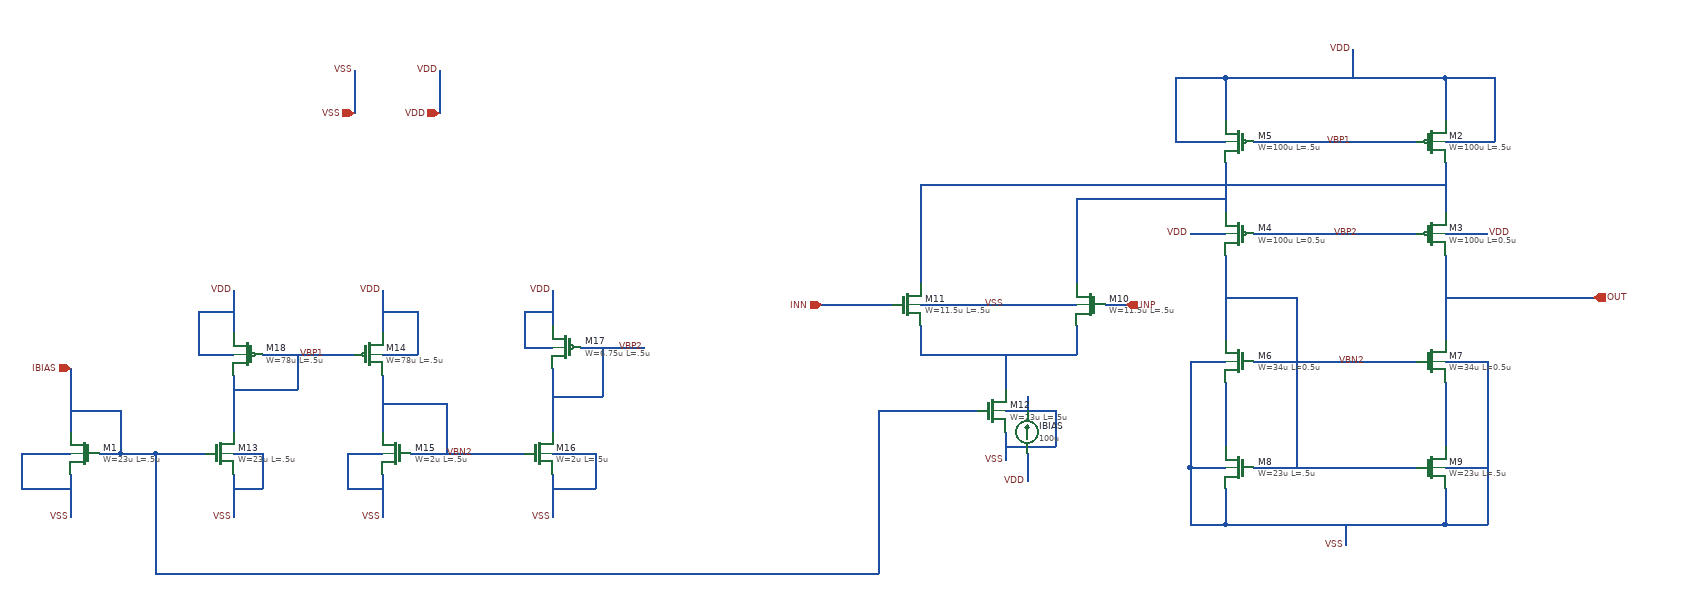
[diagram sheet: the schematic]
v {xschem version=3.4.7 file_version=1.2}
G {}
K {}
V {}
S {}
E {}
P 4 1 -990 -70 {}
P 4 1 1330 -40 {}
P 4 1 -910 -60 {}
N -410 -400 -410 -340 {lab=VDD}
N -530 -400 -530 -340 {lab=VSS}
N -930 50 -930 90 {lab=IBIAS}
N -930 90 -930 110 {lab=IBIAS}
N -930 80 -860 80 {lab=IBIAS}
N -860 80 -860 140 {lab=IBIAS}
N -890 140 -860 140 {lab=IBIAS}
N -860 140 -830 140 {lab=IBIAS}
N -930 170 -930 210 {lab=VSS}
N -1000 140 -930 140 {lab=VSS}
N -1000 140 -1000 190 {lab=VSS}
N -1000 190 -930 190 {lab=VSS}
N -930 210 -930 230 {lab=VSS}
N 700 -270 700 -200 {lab=#net1}
N 1010 -270 1010 -200 {lab=#net2}
N 740 -170 970 -170 {lab=VBP2}
N 700 -140 700 -20 {lab=#net3}
N 1010 -140 1010 -20 {lab=OUT}
N 1010 -80 1180 -80 {lab=OUT}
N 740 10 970 10 {lab=VBN2}
N 740 160 970 160 {lab=#net3}
N 1010 40 1010 100 {lab=#net4}
N 1010 100 1010 130 {lab=#net4}
N 700 40 700 130 {lab=#net5}
N 700 190 700 240 {lab=VSS}
N 700 240 1010 240 {lab=VSS}
N 1010 190 1010 240 {lab=VSS}
N 870 240 870 270 {lab=VSS}
N 700 -390 700 -330 {lab=VDD}
N 700 -390 1010 -390 {lab=VDD}
N 1010 -390 1010 -330 {lab=VDD}
N 880 -430 880 -390 {lab=VDD}
N 270 -240 1010 -240 {lab=#net2}
N 490 -220 490 -100 {lab=#net1}
N 490 -220 700 -220 {lab=#net1}
N 270 0 490 0 {lab=#net6}
N 490 -40 490 0 {lab=#net6}
N 390 0 390 50 {lab=#net6}
N 390 110 390 150 {lab=VSS}
N 290 80 350 80 {lab=IBIAS}
N 390 80 460 80 {lab=VSS}
N 460 80 460 130 {lab=VSS}
N 390 130 460 130 {lab=VSS}
N 270 -70 490 -70 {lab=VSS}
N 650 160 700 160 {lab=VSS}
N 650 160 650 240 {lab=VSS}
N 650 240 700 240 {lab=VSS}
N 650 10 700 10 {lab=VSS}
N 650 10 650 160 {lab=VSS}
N 1010 10 1070 10 {lab=VSS}
N 1010 240 1070 240 {lab=VSS}
N 1070 10 1070 240 {lab=VSS}
N 1010 160 1070 160 {lab=VSS}
N 650 -170 700 -170 {lab=VDD}
N 1010 -170 1070 -170 {lab=VDD}
N 1010 -300 1080 -300 {lab=VDD}
N 1080 -390 1080 -300 {lab=VDD}
N 1010 -390 1080 -390 {lab=VDD}
N 640 -300 700 -300 {lab=VDD}
N 630 -300 640 -300 {lab=VDD}
N 630 -390 630 -300 {lab=VDD}
N 630 -390 700 -390 {lab=VDD}
N -700 30 -700 120 {lab=VBP1}
N -700 -70 -700 -30 {lab=VDD}
N -930 20 -930 50 {lab=IBIAS}
N -700 -90 -700 -70 {lab=VDD}
N -750 0 -700 0 {lab=VDD}
N -750 -60 -750 0 {lab=VDD}
N -750 -60 -700 -60 {lab=VDD}
N -660 0 -530 0 {lab=VBP1}
N -700 50 -610 50 {lab=VBP1}
N -610 0 -610 50 {lab=VBP1}
N -830 140 -810 140 {lab=IBIAS}
N -810 140 -760 140 {lab=IBIAS}
N 270 -240 270 -100 {lab=#net2}
N 270 -40 270 0 {lab=#net6}
N -700 180 -700 230 {lab=VSS}
N 740 -300 970 -300 {lab=VBP1}
N 700 -80 800 -80 {lab=#net3}
N 800 -80 800 160 {lab=#net3}
N 130 -70 230 -70 {lab=INN}
N 530 -70 550 -70 {lab=INP}
N 550 -70 560 -70 {lab=INP}
N -700 170 -700 180 {lab=VSS}
N -700 140 -660 140 {lab=VSS}
N -660 140 -660 190 {lab=VSS}
N -700 190 -660 190 {lab=VSS}
N 1180 -80 1220 -80 {lab=OUT}
N -490 -90 -490 -30 {lab=VDD}
N -490 0 -440 0 {lab=VDD}
N -440 -60 -440 0 {lab=VDD}
N -490 -60 -440 -60 {lab=VDD}
N -490 30 -490 110 {lab=VBN2}
N -490 170 -490 230 {lab=VSS}
N -540 140 -490 140 {lab=VSS}
N -540 140 -540 190 {lab=VSS}
N -540 190 -490 190 {lab=VSS}
N -450 140 -290 140 {lab=VBN2}
N -250 20 -250 110 {lab=VBP2}
N -250 170 -250 230 {lab=VSS}
N -250 140 -190 140 {lab=VSS}
N -190 140 -190 190 {lab=VSS}
N -250 190 -190 190 {lab=VSS}
N -250 -90 -250 -40 {lab=VDD}
N -290 -10 -250 -10 {lab=VDD}
N -290 -60 -290 -10 {lab=VDD}
N -290 -60 -250 -60 {lab=VDD}
N -210 -10 -120 -10 {lab=VBP2}
N -490 70 -400 70 {lab=VBN2}
N -400 70 -400 140 {lab=VBN2}
N -250 60 -180 60 {lab=VBP2}
N -180 -10 -180 60 {lab=VBP2}
N -760 140 -740 140 {lab=IBIAS}
N -810 140 -810 310 {lab=IBIAS}
N -810 310 210 310 {lab=IBIAS}
N 210 80 210 310 {lab=IBIAS}
N 210 80 290 80 {lab=IBIAS}
N 420 60 420 80 {lab=#net1}
N 420 140 420 180 {lab=VDD}
C {lab_pin.sym} -410 -400 0 0 {name=p1 sig_type=std_logic lab=VDD}
C {lab_pin.sym} -530 -400 0 0 {name=p3 sig_type=std_logic lab=VSS}
C {symbols/nfet_03v3.sym} -910 140 0 1 {name=M1
L=.5u
W=23u
nf=1
m=1
ad="'int((nf+1)/2) * W/nf * 0.18u'"
pd="'2*int((nf+1)/2) * (W/nf + 0.18u)'"
as="'int((nf+2)/2) * W/nf * 0.18u'"
ps="'2*int((nf+2)/2) * (W/nf + 0.18u)'"
nrd="'0.18u / W'" nrs="'0.18u / W'"
sa=0 sb=0 sd=0
model=nfet_03v3
spiceprefix=X
}
C {lab_pin.sym} -930 230 0 0 {name=p5 sig_type=std_logic lab=VSS}
C {symbols/pfet_03v3.sym} 990 -300 0 0 {name=M2
L=.5u
W=100u
nf=1
m=1.5
ad="'int((nf+1)/2) * W/nf * 0.18u'"
pd="'2*int((nf+1)/2) * (W/nf + 0.18u)'"
as="'int((nf+2)/2) * W/nf * 0.18u'"
ps="'2*int((nf+2)/2) * (W/nf + 0.18u)'"
nrd="'0.18u / W'" nrs="'0.18u / W'"
sa=0 sb=0 sd=0
model=pfet_03v3
spiceprefix=X
}
C {symbols/pfet_03v3.sym} 990 -170 0 0 {name=M3
L=0.5u
W=100u
nf=1
m=1
ad="'int((nf+1)/2) * W/nf * 0.18u'"
pd="'2*int((nf+1)/2) * (W/nf + 0.18u)'"
as="'int((nf+2)/2) * W/nf * 0.18u'"
ps="'2*int((nf+2)/2) * (W/nf + 0.18u)'"
nrd="'0.18u / W'" nrs="'0.18u / W'"
sa=0 sb=0 sd=0
model=pfet_03v3
spiceprefix=X
}
C {symbols/pfet_03v3.sym} 720 -170 0 1 {name=M4
L=0.5u
W=100u
nf=1
m=1
ad="'int((nf+1)/2) * W/nf * 0.18u'"
pd="'2*int((nf+1)/2) * (W/nf + 0.18u)'"
as="'int((nf+2)/2) * W/nf * 0.18u'"
ps="'2*int((nf+2)/2) * (W/nf + 0.18u)'"
nrd="'0.18u / W'" nrs="'0.18u / W'"
sa=0 sb=0 sd=0
model=pfet_03v3
spiceprefix=X
}
C {symbols/pfet_03v3.sym} 720 -300 0 1 {name=M5
L=.5u
W=100u
nf=1
m=1.5
ad="'int((nf+1)/2) * W/nf * 0.18u'"
pd="'2*int((nf+1)/2) * (W/nf + 0.18u)'"
as="'int((nf+2)/2) * W/nf * 0.18u'"
ps="'2*int((nf+2)/2) * (W/nf + 0.18u)'"
nrd="'0.18u / W'" nrs="'0.18u / W'"
sa=0 sb=0 sd=0
model=pfet_03v3
spiceprefix=X
}
C {symbols/nfet_03v3.sym} 720 10 0 1 {name=M6
L=0.5u
W=34u
nf=1
m=1
ad="'int((nf+1)/2) * W/nf * 0.18u'"
pd="'2*int((nf+1)/2) * (W/nf + 0.18u)'"
as="'int((nf+2)/2) * W/nf * 0.18u'"
ps="'2*int((nf+2)/2) * (W/nf + 0.18u)'"
nrd="'0.18u / W'" nrs="'0.18u / W'"
sa=0 sb=0 sd=0
model=nfet_03v3
spiceprefix=X
}
C {symbols/nfet_03v3.sym} 990 10 0 0 {name=M7
L=0.5u
W=34u
nf=1
m=1
ad="'int((nf+1)/2) * W/nf * 0.18u'"
pd="'2*int((nf+1)/2) * (W/nf + 0.18u)'"
as="'int((nf+2)/2) * W/nf * 0.18u'"
ps="'2*int((nf+2)/2) * (W/nf + 0.18u)'"
nrd="'0.18u / W'" nrs="'0.18u / W'"
sa=0 sb=0 sd=0
model=nfet_03v3
spiceprefix=X
}
C {symbols/nfet_03v3.sym} 720 160 0 1 {name=M8
L=.5u
W=23u
nf=1
m=2
ad="'int((nf+1)/2) * W/nf * 0.18u'"
pd="'2*int((nf+1)/2) * (W/nf + 0.18u)'"
as="'int((nf+2)/2) * W/nf * 0.18u'"
ps="'2*int((nf+2)/2) * (W/nf + 0.18u)'"
nrd="'0.18u / W'" nrs="'0.18u / W'"
sa=0 sb=0 sd=0
model=nfet_03v3
spiceprefix=X
}
C {symbols/nfet_03v3.sym} 990 160 0 0 {name=M9
L=.5u
W=23u
nf=1
m=2
ad="'int((nf+1)/2) * W/nf * 0.18u'"
pd="'2*int((nf+1)/2) * (W/nf + 0.18u)'"
as="'int((nf+2)/2) * W/nf * 0.18u'"
ps="'2*int((nf+2)/2) * (W/nf + 0.18u)'"
nrd="'0.18u / W'" nrs="'0.18u / W'"
sa=0 sb=0 sd=0
model=nfet_03v3
spiceprefix=X
}
C {lab_pin.sym} 870 270 0 0 {name=p7 sig_type=std_logic lab=VSS}
C {lab_pin.sym} 880 -430 0 0 {name=p8 sig_type=std_logic lab=VDD}
C {symbols/nfet_03v3.sym} 510 -70 0 1 {name=M10
L=.5u
W=11.5u
nf=1
m=1
ad="'int((nf+1)/2) * W/nf * 0.18u'"
pd="'2*int((nf+1)/2) * (W/nf + 0.18u)'"
as="'int((nf+2)/2) * W/nf * 0.18u'"
ps="'2*int((nf+2)/2) * (W/nf + 0.18u)'"
nrd="'0.18u / W'" nrs="'0.18u / W'"
sa=0 sb=0 sd=0
model=nfet_03v3
spiceprefix=X
}
C {symbols/nfet_03v3.sym} 370 80 0 0 {name=M12
L=.5u
W=23u
nf=1
m=1
ad="'int((nf+1)/2) * W/nf * 0.18u'"
pd="'2*int((nf+1)/2) * (W/nf + 0.18u)'"
as="'int((nf+2)/2) * W/nf * 0.18u'"
ps="'2*int((nf+2)/2) * (W/nf + 0.18u)'"
nrd="'0.18u / W'" nrs="'0.18u / W'"
sa=0 sb=0 sd=0
model=nfet_03v3
spiceprefix=X
}
C {lab_pin.sym} 390 150 0 0 {name=p10 sig_type=std_logic lab=VSS}
C {lab_pin.sym} 390 -70 1 0 {name=p18 sig_type=std_logic lab=VSS}
C {lab_pin.sym} 650 -170 0 0 {name=p19 sig_type=std_logic lab=VDD}
C {lab_pin.sym} 1070 -170 0 1 {name=p20 sig_type=std_logic lab=VDD}
C {symbols/pfet_03v3.sym} -680 0 0 1 {name=M18
L=.5u
W=78u
nf=1
m=1
ad="'int((nf+1)/2) * W/nf * 0.18u'"
pd="'2*int((nf+1)/2) * (W/nf + 0.18u)'"
as="'int((nf+2)/2) * W/nf * 0.18u'"
ps="'2*int((nf+2)/2) * (W/nf + 0.18u)'"
nrd="'0.18u / W'" nrs="'0.18u / W'"
sa=0 sb=0 sd=0
model=pfet_03v3
spiceprefix=X
}
C {lab_pin.sym} -700 -90 0 0 {name=p31 sig_type=std_logic lab=VDD}
C {lab_pin.sym} -570 0 1 0 {name=p33 sig_type=std_logic lab=VBP1}
C {symbols/nfet_03v3.sym} 250 -70 0 0 {name=M11
L=.5u
W=11.5u
nf=1
m=1
ad="'int((nf+1)/2) * W/nf * 0.18u'"
pd="'2*int((nf+1)/2) * (W/nf + 0.18u)'"
as="'int((nf+2)/2) * W/nf * 0.18u'"
ps="'2*int((nf+2)/2) * (W/nf + 0.18u)'"
nrd="'0.18u / W'" nrs="'0.18u / W'"
sa=0 sb=0 sd=0
model=nfet_03v3
spiceprefix=X
}
C {lab_pin.sym} -700 230 0 0 {name=p12 sig_type=std_logic lab=VSS}
C {lab_pin.sym} 880 -300 1 0 {name=p13 sig_type=std_logic lab=VBP1}
C {symbols/nfet_03v3.sym} -720 140 0 0 {name=M13
L=.5u
W=23u
nf=1
m=1
ad="'int((nf+1)/2) * W/nf * 0.18u'"
pd="'2*int((nf+1)/2) * (W/nf + 0.18u)'"
as="'int((nf+2)/2) * W/nf * 0.18u'"
ps="'2*int((nf+2)/2) * (W/nf + 0.18u)'"
nrd="'0.18u / W'" nrs="'0.18u / W'"
sa=0 sb=0 sd=0
model=nfet_03v3
spiceprefix=X
}
C {symbols/pfet_03v3.sym} -510 0 0 0 {name=M14
L=.5u
W=78u
nf=1
m=1
ad="'int((nf+1)/2) * W/nf * 0.18u'"
pd="'2*int((nf+1)/2) * (W/nf + 0.18u)'"
as="'int((nf+2)/2) * W/nf * 0.18u'"
ps="'2*int((nf+2)/2) * (W/nf + 0.18u)'"
nrd="'0.18u / W'" nrs="'0.18u / W'"
sa=0 sb=0 sd=0
model=pfet_03v3
spiceprefix=X
}
C {lab_pin.sym} -490 -90 0 0 {name=p21 sig_type=std_logic lab=VDD}
C {symbols/nfet_03v3.sym} -470 140 0 1 {name=M15
L=.5u
W=2u
nf=1
m=1
ad="'int((nf+1)/2) * W/nf * 0.18u'"
pd="'2*int((nf+1)/2) * (W/nf + 0.18u)'"
as="'int((nf+2)/2) * W/nf * 0.18u'"
ps="'2*int((nf+2)/2) * (W/nf + 0.18u)'"
nrd="'0.18u / W'" nrs="'0.18u / W'"
sa=0 sb=0 sd=0
model=nfet_03v3
spiceprefix=X
}
C {lab_pin.sym} -490 230 0 0 {name=p22 sig_type=std_logic lab=VSS}
C {symbols/nfet_03v3.sym} -270 140 0 0 {name=M16
L=.5u
W=2u
nf=1
m=1
ad="'int((nf+1)/2) * W/nf * 0.18u'"
pd="'2*int((nf+1)/2) * (W/nf + 0.18u)'"
as="'int((nf+2)/2) * W/nf * 0.18u'"
ps="'2*int((nf+2)/2) * (W/nf + 0.18u)'"
nrd="'0.18u / W'" nrs="'0.18u / W'"
sa=0 sb=0 sd=0
model=nfet_03v3
spiceprefix=X
}
C {symbols/pfet_03v3.sym} -230 -10 0 1 {name=M17
L=.5u
W=6.75u
nf=1
m=1
ad="'int((nf+1)/2) * W/nf * 0.18u'"
pd="'2*int((nf+1)/2) * (W/nf + 0.18u)'"
as="'int((nf+2)/2) * W/nf * 0.18u'"
ps="'2*int((nf+2)/2) * (W/nf + 0.18u)'"
nrd="'0.18u / W'" nrs="'0.18u / W'"
sa=0 sb=0 sd=0
model=pfet_03v3
spiceprefix=X
}
C {lab_pin.sym} -250 230 0 0 {name=p23 sig_type=std_logic lab=VSS}
C {lab_pin.sym} -250 -90 0 0 {name=p24 sig_type=std_logic lab=VDD}
C {lab_pin.sym} -360 140 1 1 {name=p25 sig_type=std_logic lab= VBN2}
C {lab_pin.sym} -120 -10 1 0 {name=p26 sig_type=std_logic lab=VBP2}
C {lab_pin.sym} 900 10 1 1 {name=p15 sig_type=std_logic lab= VBN2}
C {lab_pin.sym} 890 -170 3 0 {name=p16 sig_type=std_logic lab=VBP2}
C {iopin.sym} -930 20 3 0 {name=p2 lab=IBIAS}
C {iopin.sym} -530 -340 1 0 {name=p4 lab=VSS}
C {iopin.sym} -410 -340 1 0 {name=p27 lab=VDD}
C {iopin.sym} 130 -70 2 0 {name=p14 lab=INN}
C {iopin.sym} 560 -70 2 1 {name=p17 lab=INP}
C {iopin.sym} 1220 -80 2 1 {name=p6 lab=OUT}
C {isource.sym} 420 110 2 0 {name=IBIAS value=100u}
C {lab_pin.sym} 420 180 0 0 {name=p9 sig_type=std_logic lab=VDD}
